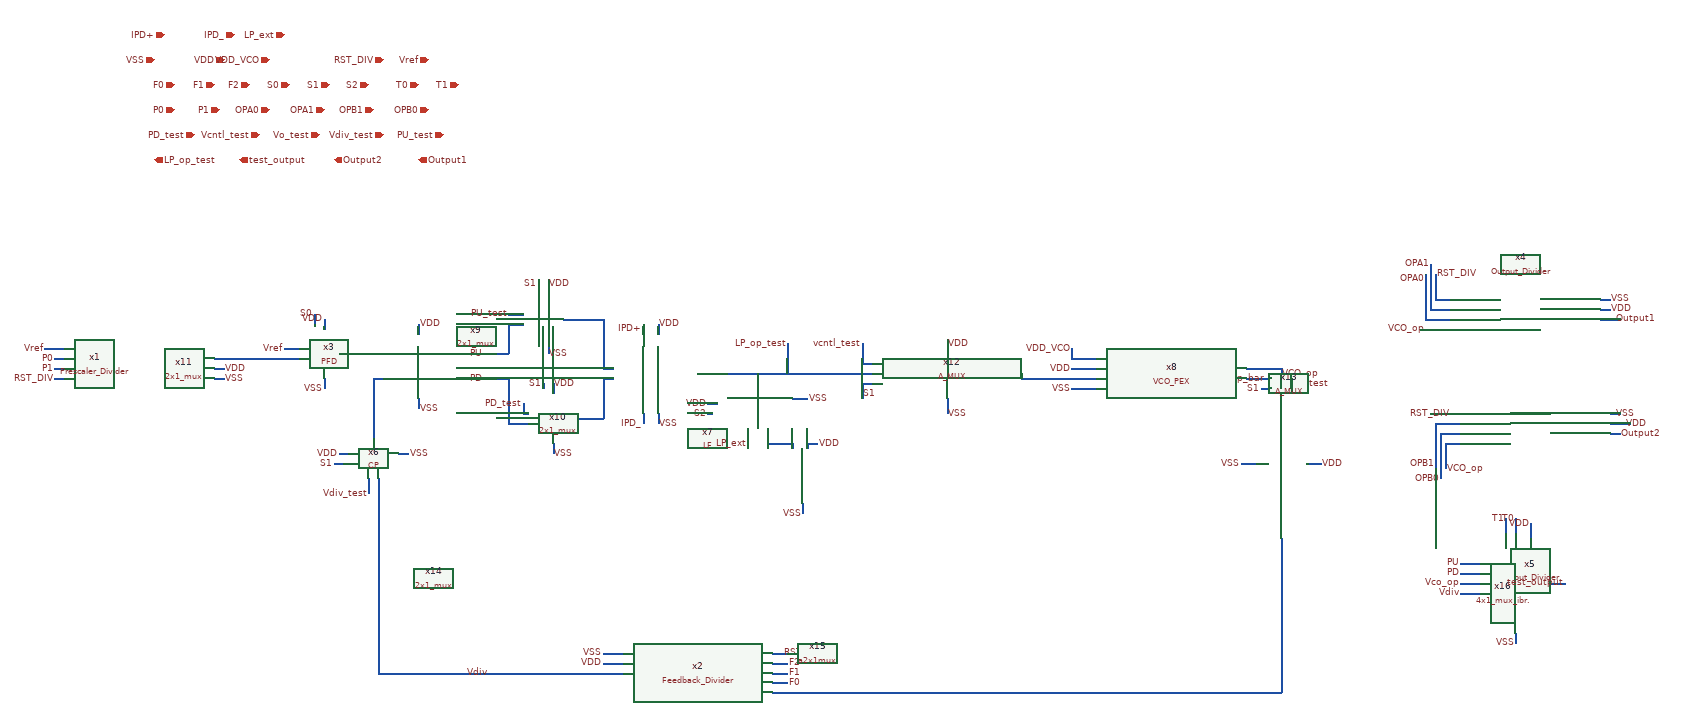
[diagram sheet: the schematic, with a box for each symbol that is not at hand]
v {xschem version=3.1.0 file_version=1.2
}
G {}
K {}
V {}
S {}
E {}
N 310 -950 330 -950 {
lab=P0}
N 310 -930 330 -930 {
lab=P1}
N 310 -910 330 -910 {
lab=RST_DIV}
N 630 -910 650 -910 {
lab=VSS}
N 630 -930 650 -930 {
lab=VDD}
N 1040 -1020 1040 -1000 {
lab=VDD}
N 1040 -870 1040 -850 {
lab=VSS}
N 950 -960 970 -960 {
lab=#net1}
N 950 -910 970 -910 {
lab=#net2}
N 1110 -910 1130 -910 {
lab=PD}
N 1130 -960 1220 -960 {
lab=PU}
N 1130 -910 1220 -910 {
lab=PD}
N 1160 -320 1450 -320 {
lab=Vdiv}
N 2350 -950 2390 -950 {
lab=VDD_VCO}
N 1110 -960 1130 -960 {
lab=PU}
N 2350 -970 2350 -950 {
lab=VDD_VCO}
N 1410 -360 1450 -360 {
lab=VSS}
N 1410 -340 1450 -340 {
lab=VDD}
N 1750 -340 1780 -340 {
lab=F2}
N 1750 -360 1780 -360 {
lab=RST_DIV}
N 2390 -950 2400 -950 {
lab=VDD_VCO}
N 1750 -300 1780 -300 {
lab=F0}
N 1750 -320 1780 -320 {
lab=F1}
N 3080 -1070 3110 -1070 {
lab=RST_DIV}
N 3080 -1120 3080 -1070 {
lab=RST_DIV}
N 3050 -1010 3110 -1010 {
lab=VCO_op}
N 3070 -1050 3110 -1050 {
lab=OPA1}
N 3070 -1120 3070 -1050 {
lab=OPA1}
N 3060 -1030 3110 -1030 {
lab=OPA0}
N 3060 -1120 3060 -1030 {
lab=OPA0}
N 3410 -1070 3430 -1070 {
lab=VSS}
N 3410 -1050 3430 -1050 {
lab=VDD}
N 3410 -1030 3450 -1030 {
lab=Output1}
N 3070 -1140 3070 -1120 {
lab=OPA1}
N 3100 -780 3130 -780 {
lab=VCO_op}
N 3100 -780 3100 -730 {
lab=VCO_op}
N 3070 -840 3130 -840 {
lab=RST_DIV}
N 3090 -800 3130 -800 {
lab=OPB0}
N 3090 -800 3090 -730 {
lab=OPB0}
N 3080 -820 3130 -820 {
lab=OPB1}
N 3080 -820 3080 -730 {
lab=OPB1}
N 3430 -840 3450 -840 {
lab=VSS}
N 3430 -800 3450 -800 {
lab=Output2}
N 3430 -820 3470 -820 {
lab=VDD}
N 3090 -730 3090 -710 {
lab=OPB0}
N 1520 -1020 1520 -1000 {
lab=VDD}
N 1520 -840 1520 -820 {
lab=VSS}
N 1410 -930 1430 -930 {
lab=#net3}
N 1410 -910 1430 -910 {
lab=#net4}
N 1490 -1020 1490 -1000 {
lab=IPD+}
N 1490 -840 1490 -820 {
lab=IPD_}
N 720 -950 750 -950 {
lab=#net5}
N 290 -970 320 -970 {
lab=Vref}
N 630 -950 700 -950 {
lab=#net5}
N 700 -950 720 -950 {
lab=#net5}
N 320 -970 330 -970 {
lab=Vref}
N 1220 -910 1220 -820 {
lab=PD}
N 1220 -820 1260 -820 {
lab=PD}
N 1250 -840 1260 -840 {
lab=PD_test}
N 1250 -860 1250 -840 {
lab=PD_test}
N 1220 -1020 1220 -960 {
lab=PU}
N 1220 -1020 1250 -1020 {
lab=PU}
N 1300 -980 1300 -960 {
lab=VSS}
N 1290 -900 1290 -890 {
lab=S1}
N 1310 -900 1310 -880 {
lab=VDD}
N 1330 -1030 1410 -1030 {
lab=#net3}
N 1410 -1030 1410 -960 {
lab=#net3}
N 1410 -910 1410 -830 {
lab=#net4}
N 1340 -830 1410 -830 {
lab=#net4}
N 1410 -960 1410 -930 {
lab=#net3}
N 1280 -1110 1280 -1090 {
lab=S1}
N 1300 -1110 1300 -1080 {
lab=VDD}
N 1220 -1040 1250 -1040 {
lab=PU_test}
N 1310 -780 1310 -760 {
lab=VSS}
N 850 -910 850 -890 {
lab=VSS}
N 850 -1030 850 -1010 {
lab=VDD}
N 830 -1040 830 -1020 {
lab=S0}
N 750 -950 800 -950 {
lab=#net5}
N 770 -970 800 -970 {
lab=Vref}
N 2100 -990 2100 -970 {
lab=VDD}
N 2100 -870 2100 -840 {
lab=VSS}
N 1930 -940 1950 -940 {
lab=vcntl_test}
N 1930 -980 1930 -940 {
lab=vcntl_test}
N 1930 -900 1950 -900 {
lab=S1}
N 1930 -900 1930 -870 {
lab=S1}
N 2790 -910 2790 -890 {
lab=Vo_test}
N 2770 -300 2770 -290 {
lab=#net6}
N 2690 -740 2720 -740 {
lab=VSS}
N 2820 -740 2850 -740 {
lab=VDD}
N 2730 -890 2750 -890 {
lab=S1}
N 2770 -290 2770 -280 {
lab=#net6}
N 2420 -280 2770 -280 {
lab=#net6}
N 1750 -280 2420 -280 {
lab=#net6}
N 2250 -910 2400 -910 {
lab=#net7}
N 2250 -920 2250 -910 {
lab=#net7}
N 2350 -930 2400 -930 {
lab=VDD}
N 2350 -890 2400 -890 {
lab=VSS}
N 2700 -930 2770 -930 {
lab=VCO_op}
N 2700 -910 2750 -910 {
lab=VCO_op_bar}
N 2770 -930 2770 -890 {
lab=VCO_op}
N 880 -960 940 -960 {
lab=#net1}
N 1000 -760 1020 -760 {
lab=VSS}
N 880 -760 900 -760 {
lab=VDD}
N 870 -740 890 -740 {
lab=S1}
N 960 -710 960 -660 {
lab=Vdiv}
N 940 -710 940 -680 {
lab=Vdiv_test}
N 950 -850 950 -790 {
lab=#net2}
N 960 -660 960 -610 {
lab=Vdiv}
N 950 -910 950 -850 {
lab=#net2}
N 940 -960 950 -960 {
lab=#net1}
N 1810 -660 1810 -640 {
lab=VSS}
N 1820 -780 1820 -770 {
lab=VDD}
N 1820 -780 1840 -780 {
lab=VDD}
N 1620 -860 1640 -860 {
lab=VDD}
N 1790 -870 1820 -870 {
lab=VSS}
N 1700 -810 1700 -780 {
lab=LP_ext}
N 1790 -780 1790 -770 {
lab=#net8}
N 1740 -780 1790 -780 {
lab=#net8}
N 1740 -810 1740 -780 {
lab=#net8}
N 1720 -920 1720 -910 {
lab=LP_op_test}
N 960 -320 1160 -320 {
lab=Vdiv}
N 960 -610 960 -490 {
lab=Vdiv}
N 2770 -420 2770 -300 {
lab=#net6}
N 960 -490 960 -320 {
lab=Vdiv}
N 2770 -590 2770 -430 {
lab=#net6}
N 2770 -430 2770 -420 {
lab=#net6}
N 1620 -840 1630 -840 {
lab=S2}
N 1600 -920 1950 -920 {
lab=LP_op_test}
N 3130 -540 3170 -540 {
lab=PU}
N 3130 -520 3170 -520 {
lab=PD}
N 3130 -500 3170 -500 {
lab=Vco_op}
N 3130 -480 3170 -480 {
lab=Vdiv}
N 1780 -980 1780 -920 {
lab=LP_op_test}
N 3270 -620 3270 -590 {
lab=VDD}
N 3240 -630 3240 -600 {
lab=T0}
N 3220 -630 3220 -600 {
lab=T1}
N 3240 -400 3240 -380 {
lab=VSS}
N 3310 -500 3340 -500 {
lab=test_output}
C {devices/ipin.sym} 860 -1500 0 0 {name=p45 lab=S1}
C {devices/ipin.sym} 780 -1500 0 0 {name=p46 lab=S0}
C {devices/ipin.sym} 1040 -1500 0 0 {name=p47 lab=T0}
C {devices/ipin.sym} 1120 -1500 0 0 {name=p48 lab=T1}
C {devices/iopin.sym} 650 -1550 0 0 {name=p58 lab=VDD}
C {devices/iopin.sym} 740 -1550 0 0 {name=p59 lab=VDD_VCO}
C {devices/ipin.sym} 1060 -1550 0 0 {name=p60 lab=Vref}
C {devices/ipin.sym} 630 -1500 0 0 {name=p62 lab=F1}
C {devices/ipin.sym} 700 -1500 0 0 {name=p63 lab=F2}
C {devices/ipin.sym} 550 -1450 0 0 {name=p64 lab=P0}
C {devices/ipin.sym} 640 -1450 0 0 {name=p65 lab=P1}
C {devices/ipin.sym} 740 -1450 0 0 {name=p66 lab=OPA0}
C {devices/ipin.sym} 970 -1550 0 0 {name=p67 lab=RST_DIV}
C {devices/ipin.sym} 550 -1500 0 0 {name=p68 lab=F0}
C {devices/ipin.sym} 850 -1450 0 0 {name=p69 lab=OPA1}
C {devices/ipin.sym} 950 -1450 0 0 {name=p70 lab=OPB1}
C {devices/ipin.sym} 1060 -1450 0 0 {name=p71 lab=OPB0}
C {devices/ipin.sym} 970 -1400 0 0 {name=p72 lab=Vdiv_test}
C {devices/ipin.sym} 1090 -1400 0 0 {name=p73 lab=PU_test}
C {devices/ipin.sym} 590 -1400 0 0 {name=p74 lab=PD_test}
C {devices/ipin.sym} 720 -1400 0 0 {name=p75 lab=Vcntl_test}
C {devices/ipin.sym} 840 -1400 0 0 {name=p76 lab=Vo_test}
C {devices/opin.sym} 510 -1350 0 0 {name=p77 lab=LP_op_test}
C {devices/opin.sym} 680 -1350 0 0 {name=p78 lab=test_output}
C {devices/opin.sym} 870 -1350 0 0 {name=p79 lab=Output2}
C {devices/opin.sym} 1040 -1350 0 0 {name=p80 lab=Output1}
C {devices/iopin.sym} 510 -1550 0 0 {name=p57 lab=VSS}
C {devices/lab_pin.sym} 310 -930 0 0 {name=p139 sig_type=std_logic lab=P1}
C {devices/lab_pin.sym} 310 -950 0 0 {name=p140 sig_type=std_logic lab=P0}
C {devices/lab_pin.sym} 290 -970 0 0 {name=p141 sig_type=std_logic lab=Vref
}
C {devices/lab_pin.sym} 650 -910 2 0 {name=p142 sig_type=std_logic lab=VSS}
C {devices/lab_pin.sym} 650 -930 2 0 {name=p143 sig_type=std_logic lab=VDD}
C {devices/lab_pin.sym} 310 -910 0 0 {name=p144 sig_type=std_logic lab=RST_DIV}
C {PFD.sym} 750 -750 0 0 {name=x3}
C {devices/lab_pin.sym} 1040 -1020 2 0 {name=p9 sig_type=std_logic lab=VDD}
C {devices/lab_wire.sym} 1040 -850 2 0 {name=p10 sig_type=std_logic lab=VSS}
C {devices/lab_pin.sym} 1180 -320 1 0 {name=p28 sig_type=std_logic lab=Vdiv
}
C {devices/lab_pin.sym} 2350 -970 0 0 {name=p12 sig_type=std_logic lab=VDD_VCO}
C {devices/lab_pin.sym} 2740 -910 1 0 {name=p13 sig_type=std_logic lab=VCO_op_bar
}
C {devices/lab_pin.sym} 1410 -340 0 0 {name=p14 sig_type=std_logic lab=VDD}
C {devices/lab_wire.sym} 1410 -360 1 0 {name=p15 sig_type=std_logic lab=VSS}
C {devices/lab_pin.sym} 1780 -980 1 0 {name=p19 sig_type=std_logic lab=LP_op_test
}
C {devices/lab_pin.sym} 1170 -960 1 0 {name=p20 sig_type=std_logic lab=PU}
C {devices/lab_pin.sym} 1170 -910 1 0 {name=p21 sig_type=std_logic lab=PD}
C {Feedback_Divider.sym} 1600 -320 0 1 {name=x2}
C {devices/lab_pin.sym} 1780 -300 2 0 {name=p22 sig_type=std_logic lab=F0}
C {devices/lab_pin.sym} 1780 -320 2 0 {name=p23 sig_type=std_logic lab=F1}
C {devices/lab_pin.sym} 1780 -340 2 0 {name=p24 sig_type=std_logic lab=F2}
C {devices/lab_pin.sym} 3430 -1050 2 0 {name=p32 sig_type=std_logic lab=VDD}
C {devices/lab_pin.sym} 3430 -1070 2 0 {name=p33 sig_type=std_logic lab=VSS}
C {devices/lab_wire.sym} 3060 -1110 0 0 {name=p82 sig_type=std_logic lab=OPA0}
C {devices/lab_wire.sym} 3070 -1140 0 0 {name=p83 sig_type=std_logic lab=OPA1}
C {devices/lab_pin.sym} 3080 -1120 2 0 {name=p34 sig_type=std_logic lab=RST_DIV}
C {devices/lab_pin.sym} 3440 -1030 2 0 {name=p84 sig_type=std_logic lab=Output1}
C {devices/lab_pin.sym} 3460 -820 0 1 {name=p85 sig_type=std_logic lab=VDD}
C {devices/lab_pin.sym} 3440 -840 0 1 {name=p86 sig_type=std_logic lab=VSS}
C {devices/lab_wire.sym} 3080 -740 2 1 {name=p87 sig_type=std_logic lab=OPB1}
C {devices/lab_wire.sym} 3090 -710 2 1 {name=p88 sig_type=std_logic lab=OPB0}
C {devices/lab_pin.sym} 3450 -800 0 1 {name=p90 sig_type=std_logic lab=Output2}
C {Output_Divider.sym} 3280 -810 0 0 {name=x5}
C {devices/lab_pin.sym} 3110 -840 1 0 {name=p35 sig_type=std_logic lab=RST_DIV}
C {devices/lab_pin.sym} 3100 -730 2 0 {name=p37 sig_type=std_logic lab=VCO_op
}
C {devices/lab_pin.sym} 3060 -1010 2 1 {name=p40 sig_type=std_logic lab=VCO_op
}
C {devices/lab_pin.sym} 1770 -360 2 0 {name=p39 sig_type=std_logic lab=RST_DIV}
C {devices/lab_wire.sym} 1520 -820 2 0 {name=p1 sig_type=std_logic lab=VSS}
C {devices/lab_pin.sym} 1520 -1020 2 0 {name=p50 sig_type=std_logic lab=VDD}
C {CP.sym} 940 -720 0 0 {name=x6}
C {devices/lab_wire.sym} 1490 -1010 0 0 {name=p52 sig_type=std_logic lab=IPD+}
C {devices/lab_wire.sym} 1490 -820 0 0 {name=p53 sig_type=std_logic lab=IPD_}
C {Output_Divider.sym} 3260 -1040 0 0 {name=x4}
C {2x1_mux.sym} 1050 -910 0 0 {name=x9}
C {2x1_mux.sym} 1060 -710 0 0 {name=x10}
C {devices/lab_pin.sym} 1220 -1040 0 0 {name=p2 sig_type=std_logic lab=PU_test
}
C {devices/lab_pin.sym} 1250 -860 1 0 {name=p3 sig_type=std_logic lab=PD_test
}
C {devices/lab_pin.sym} 1300 -1100 2 0 {name=p4 sig_type=std_logic lab=VDD}
C {devices/lab_pin.sym} 1310 -900 2 0 {name=p5 sig_type=std_logic lab=VDD}
C {devices/lab_wire.sym} 1310 -760 2 0 {name=p6 sig_type=std_logic lab=VSS}
C {devices/lab_wire.sym} 1300 -960 2 0 {name=p7 sig_type=std_logic lab=VSS}
C {devices/lab_pin.sym} 1280 -1100 1 0 {name=p106 sig_type=std_logic lab=S1}
C {devices/lab_pin.sym} 1290 -900 1 0 {name=p8 sig_type=std_logic lab=S1}
C {2x1_mux.sym} 600 -840 0 0 {name=x11}
C {devices/lab_wire.sym} 850 -890 3 0 {name=p11 sig_type=std_logic lab=VSS}
C {devices/lab_pin.sym} 850 -1030 3 1 {name=p16 sig_type=std_logic lab=VDD}
C {devices/lab_pin.sym} 830 -1040 1 0 {name=p17 sig_type=std_logic lab=S0}
C {devices/lab_pin.sym} 770 -970 1 0 {name=p18 sig_type=std_logic lab=Vref
}
C {A_MUX.sym} 2100 -920 0 0 {name=x12}
C {devices/lab_pin.sym} 2100 -980 2 0 {name=p25 sig_type=std_logic lab=VDD}
C {devices/lab_wire.sym} 2100 -840 2 0 {name=p26 sig_type=std_logic lab=VSS}
C {devices/lab_pin.sym} 1930 -880 2 0 {name=p27 sig_type=std_logic lab=S1}
C {devices/lab_pin.sym} 1930 -980 0 0 {name=p29 sig_type=std_logic lab=vcntl_test
}
C {devices/lab_pin.sym} 2770 -920 2 0 {name=p30 sig_type=std_logic lab=VCO_op
}
C {devices/lab_pin.sym} 2790 -900 2 0 {name=p31 sig_type=std_logic lab=Vo_test
}
C {A_MUX.sym} 2770 -740 1 0 {name=x13}
C {devices/lab_pin.sym} 2730 -890 0 0 {name=p36 sig_type=std_logic lab=S1}
C {devices/lab_wire.sym} 2690 -740 0 0 {name=p38 sig_type=std_logic lab=VSS}
C {devices/lab_pin.sym} 2850 -740 2 0 {name=p41 sig_type=std_logic lab=VDD}
C {devices/lab_pin.sym} 2350 -930 0 0 {name=p42 sig_type=std_logic lab=VDD}
C {devices/lab_wire.sym} 2350 -890 2 1 {name=p89 sig_type=std_logic lab=VSS}
C {2x1_mux.sym} 1070 -510 3 0 {name=x14}
C {devices/lab_wire.sym} 1020 -760 2 0 {name=p91 sig_type=std_logic lab=VSS}
C {devices/lab_pin.sym} 880 -760 2 1 {name=p92 sig_type=std_logic lab=VDD}
C {devices/lab_pin.sym} 870 -740 0 0 {name=p93 sig_type=std_logic lab=S1}
C {devices/lab_pin.sym} 940 -680 0 0 {name=p94 sig_type=std_logic lab=Vdiv_test

}
C {devices/lab_wire.sym} 1810 -640 2 1 {name=p43 sig_type=std_logic lab=VSS}
C {devices/lab_wire.sym} 1840 -780 0 1 {name=p98 sig_type=std_logic lab=VDD}
C {devices/lab_wire.sym} 1820 -870 2 0 {name=p99 sig_type=std_logic lab=VSS}
C {devices/lab_wire.sym} 1620 -860 2 1 {name=p100 sig_type=std_logic lab=VDD}
C {devices/lab_wire.sym} 1620 -840 1 1 {name=p44 sig_type=std_logic lab=S2}
C {LF.sym} 1950 -610 0 1 {name=x7}
C {a2x1mux.sym} 1880 -490 3 0 {name=x15}
C {VCO_PEX.sym} 2550 -920 0 0 {name=x8}
C {4x1_mux_ibr..sym} 2890 -390 0 0 {name=x16}
C {devices/lab_pin.sym} 3130 -540 0 0 {name=p97 sig_type=std_logic lab=PU}
C {devices/lab_pin.sym} 3130 -520 0 0 {name=p54 sig_type=std_logic lab=PD}
C {devices/lab_pin.sym} 3130 -500 0 0 {name=p55 sig_type=std_logic lab=Vco_op
}
C {devices/lab_pin.sym} 3130 -480 0 0 {name=p105 sig_type=std_logic lab=Vdiv
}
C {devices/lab_pin.sym} 3220 -630 1 0 {name=p107 sig_type=std_logic lab=T1}
C {devices/lab_pin.sym} 3240 -630 1 0 {name=p108 sig_type=std_logic lab=T0}
C {devices/lab_pin.sym} 3270 -620 3 1 {name=p109 sig_type=std_logic lab=VDD}
C {devices/lab_wire.sym} 3240 -380 3 0 {name=p110 sig_type=std_logic lab=VSS}
C {devices/lab_pin.sym} 3340 -500 1 1 {name=p111 sig_type=std_logic lab=test_output}
C {devices/ipin.sym} 940 -1500 0 0 {name=p56 lab=S2}
C {Prescaler_Divider.sym} 480 -940 2 1 {name=x1}
C {devices/iopin.sym} 530 -1600 0 0 {name=p49 lab=IPD+}
C {devices/iopin.sym} 670 -1600 0 0 {name=p61 lab=IPD_}
C {devices/lab_pin.sym} 1700 -780 0 0 {name=p51 sig_type=std_logic lab=LP_ext

}
C {devices/iopin.sym} 770 -1600 0 0 {name=p81 lab=LP_ext}
